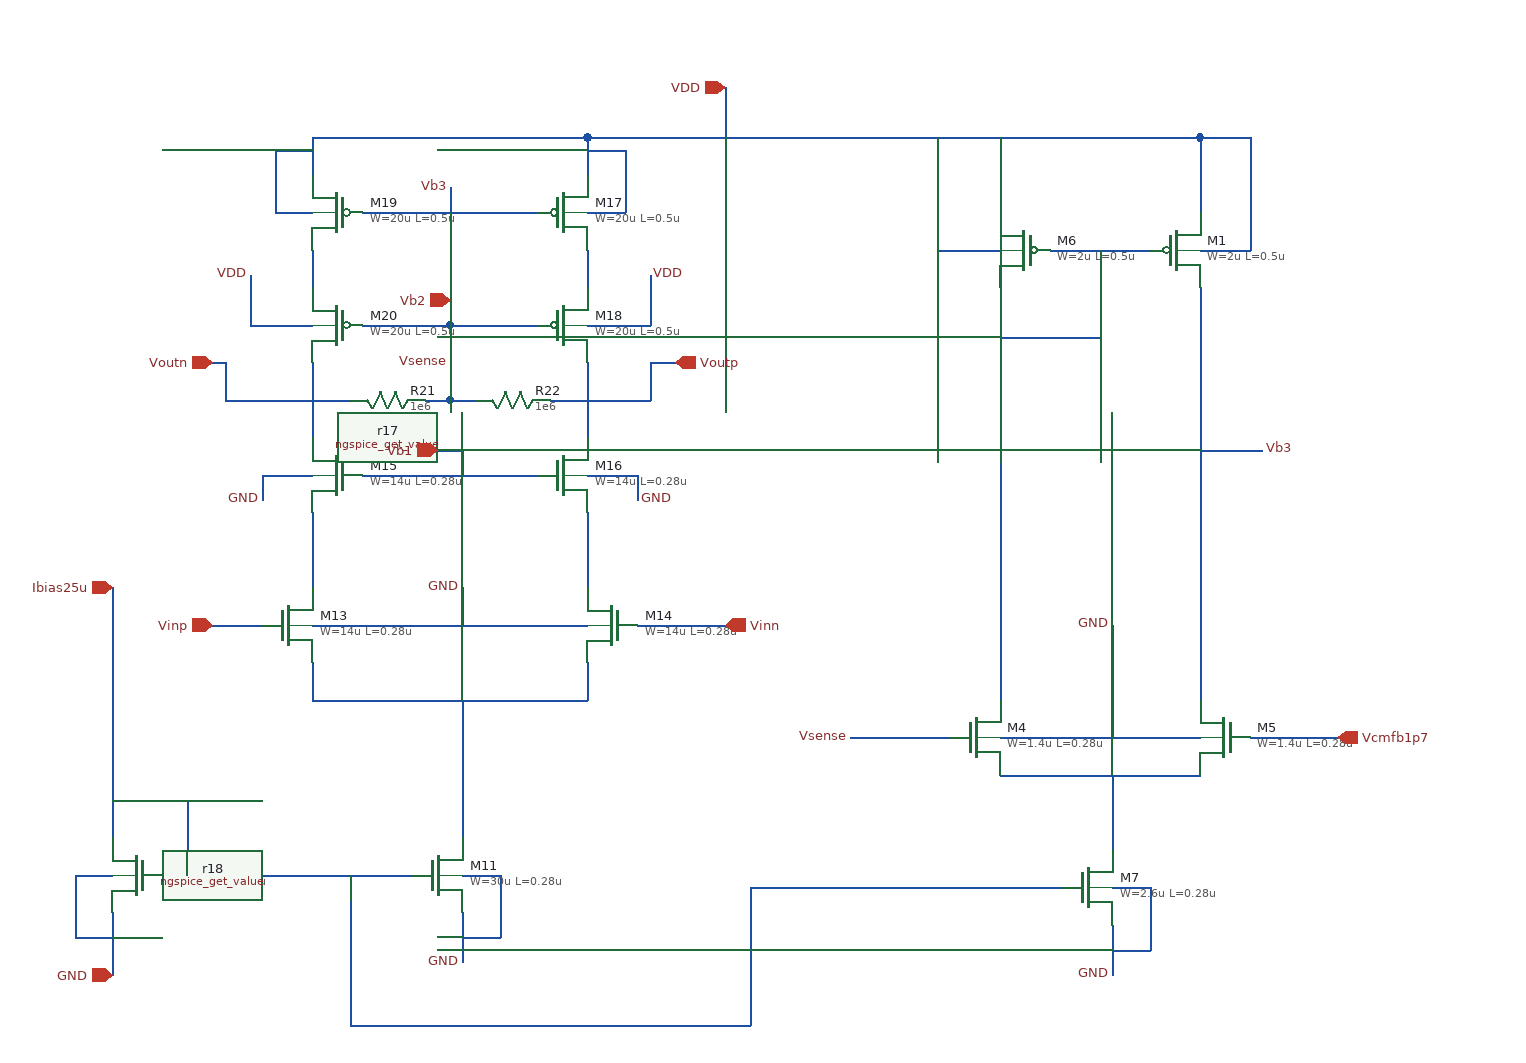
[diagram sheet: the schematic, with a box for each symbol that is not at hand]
v {xschem version=3.4.8RC file_version=1.3}
G {}
K {}
V {}
S {}
F {}
E {}
N 360 -840 490 -840 {lab=Vb3
}
N 490 -840 500 -840 {lab=Vb3
}
N 360 -750 430 -750 {lab=Vb2
}
N 430 -750 500 -750 {lab=Vb2
}
N 540 -810 540 -780 {lab=#net1
}
N 320 -810 320 -780 {lab=#net2
}
N 320 -900 320 -870 {lab=VDD
}
N 320 -900 540 -900 {lab=VDD
}
N 540 -900 540 -870 {lab=VDD
}
N 290 -840 320 -840 {lab=VDD
}
N 290 -890 290 -840 {lab=VDD
}
N 290 -890 320 -890 {lab=VDD
}
N 540 -840 570 -840 {lab=VDD
}
N 570 -890 570 -840 {lab=VDD
}
N 540 -890 570 -890 {lab=VDD
}
N 360 -630 500 -630 {lab=Vb1
}
N 320 -720 320 -660 {lab=Voutn
}
N 540 -720 540 -660 {lab=Voutp
}
N 320 -600 320 -540 {lab=#net3
}
N 540 -600 540 -540 {lab=#net4
}
N 260 -510 280 -510 {lab=Vinp
}
N 580 -510 650 -510 {lab=Vinn
}
N 200 -310 400 -310 {lab=Ibias25u
}
N 320 -470 320 -450 {lab=#net5
}
N 320 -450 540 -450 {lab=#net5
}
N 540 -480 540 -450 {lab=#net5
}
N 320 -480 320 -470 {lab=#net5
}
N 440 -450 440 -400 {lab=#net5
}
N 160 -540 160 -400 {lab=Ibias25u
}
N 160 -370 180 -370 {lab=Ibias25u
}
N 180 -370 220 -370 {lab=Ibias25u
}
N 160 -280 160 -230 {lab=GND
}
N 440 -280 440 -240 {lab=GND
}
N 440 -310 470 -310 {lab=GND
}
N 470 -310 470 -260 {lab=GND
}
N 440 -260 470 -260 {lab=GND
}
N 130 -310 160 -310 {lab=GND
}
N 130 -310 130 -260 {lab=GND
spice_ignore=short}
N 130 -260 160 -260 {lab=GND
}
N 320 -510 540 -510 {lab=GND
}
N 280 -630 320 -630 {lab=GND
}
N 280 -630 280 -610 {lab=GND
}
N 540 -630 580 -630 {lab=GND
}
N 580 -630 580 -610 {lab=GND
}
N 270 -750 320 -750 {lab=VDD
}
N 270 -790 270 -750 {lab=VDD
}
N 540 -750 590 -750 {lab=VDD
}
N 590 -790 590 -750 {lab=VDD
}
N 430 -860 430 -840 {lab=Vb3
}
N 430 -770 430 -750 {lab=Vb2
}
N 440 -650 440 -630 {lab=Vb1
}
N 250 -720 250 -690 {lab=Voutn
}
N 590 -720 610 -720 {lab=Voutp
}
N 590 -720 590 -690 {lab=Voutp
}
N 160 -400 160 -340 {lab=Ibias25u
}
N 220 -370 220 -310 {lab=Ibias25u
}
N 440 -400 440 -340 {lab=#net5
}
N 330 -690 350 -690 {lab=Voutn
}
N 320 -690 330 -690 {lab=Voutn
}
N 510 -690 540 -690 {lab=Voutp
}
N 430 -720 430 -690 {lab=Vsense
spice_ignore=short}
N 410 -690 430 -690 {lab=Vsense
spice_ignore=short}
N 430 -690 450 -690 {lab=Vsense
spice_ignore=short}
N 1030 -900 1030 -840 {lab=VDD}
N 540 -900 860 -900 {lab=VDD}
N 860 -900 960 -900 {lab=VDD}
N 1030 -650 1080 -650 {lab=#net6}
N 910 -810 990 -810 {lab=#net7}
N 870 -900 870 -840 {lab=VDD}
N 960 -270 960 -230 {lab=GND
}
N 960 -300 990 -300 {lab=GND
}
N 990 -300 990 -250 {lab=GND
}
N 960 -250 990 -250 {lab=GND
}
N 350 -310 350 -190 {lab=Ibias25u}
N 350 -190 670 -190 {lab=Ibias25u}
N 670 -300 670 -190 {lab=Ibias25u}
N 840 -300 920 -300 {lab=Ibias25u}
N 750 -300 840 -300 {lab=Ibias25u}
N 670 -300 750 -300 {lab=Ibias25u}
N 750 -420 830 -420 {lab=Vsense}
N 1070 -420 1140 -420 {lab=Vcmfb1p7}
N 890 -390 1030 -390 {lab=#net8}
N 960 -390 960 -330 {lab=#net8}
N 1030 -780 1030 -450 {lab=#net6}
N 870 -780 870 -450 {lab=#net7}
N 870 -390 890 -390 {lab=#net8}
N 960 -900 1030 -900 {lab=VDD}
N 820 -810 870 -810 {lab=VDD}
N 820 -900 820 -810 {lab=VDD}
N 1030 -810 1070 -810 {lab=VDD}
N 1070 -900 1070 -810 {lab=VDD}
N 1030 -900 1070 -900 {lab=VDD}
N 870 -420 1030 -420 {lab=GND}
N 950 -810 950 -740 {lab=#net7}
N 870 -740 950 -740 {lab=#net7}
N 650 -940 650 -900 {lab=VDD}
N 250 -690 320 -690 {lab=Voutn}
N 540 -690 590 -690 {lab=Voutp}
N 240 -720 250 -720 {lab=Voutn}
N 420 -650 440 -650 {lab=Vb1}
N 240 -510 260 -510 {lab=Vinp}
N 960 -510 960 -420 {lab=GND}
N 440 -540 440 -510 {lab=GND}
C {lab_pin.sym} 430 -860 0 0 {name=p23 sig_type=std_logic lab=Vb3
}
C {symbols/nfet_03v3.sym} 420 -310 0 0 {name=M11
L=0.28u
W=30u
nf=1
m=1
ad="'int((nf+1)/2) * W/nf * 0.18u'"
pd="'2*int((nf+1)/2) * (W/nf + 0.18u)'"
as="'int((nf+2)/2) * W/nf * 0.18u'"
ps="'2*int((nf+2)/2) * (W/nf + 0.18u)'"
nrd="'0.18u / W'" nrs="'0.18u / W'"
sa=0 sb=0 sd=0
model=nfet_03v3
spiceprefix=X
}
C {symbols/nfet_03v3.sym} 180 -310 0 1 {name=M12
L=0.28u
W=2.6u
nf=1
m=1
ad="'int((nf+1)/2) * W/nf * 0.18u'"
pd="'2*int((nf+1)/2) * (W/nf + 0.18u)'"
as="'int((nf+2)/2) * W/nf * 0.18u'"
ps="'2*int((nf+2)/2) * (W/nf + 0.18u)'"
nrd="'0.18u / W'" nrs="'0.18u / W'"
sa=0 sb=0 sd=0
model=nfet_03v3
spiceprefix=X
}
C {symbols/nfet_03v3.sym} 300 -510 0 0 {name=M13
L=0.28u
W=14u
nf=1
m=1
ad="'int((nf+1)/2) * W/nf * 0.18u'"
pd="'2*int((nf+1)/2) * (W/nf + 0.18u)'"
as="'int((nf+2)/2) * W/nf * 0.18u'"
ps="'2*int((nf+2)/2) * (W/nf + 0.18u)'"
nrd="'0.18u / W'" nrs="'0.18u / W'"
sa=0 sb=0 sd=0
model=nfet_03v3
spiceprefix=X
}
C {symbols/nfet_03v3.sym} 560 -510 0 1 {name=M14
L=0.28u
W=14u
nf=1
m=1
ad="'int((nf+1)/2) * W/nf * 0.18u'"
pd="'2*int((nf+1)/2) * (W/nf + 0.18u)'"
as="'int((nf+2)/2) * W/nf * 0.18u'"
ps="'2*int((nf+2)/2) * (W/nf + 0.18u)'"
nrd="'0.18u / W'" nrs="'0.18u / W'"
sa=0 sb=0 sd=0
model=nfet_03v3
spiceprefix=X
}
C {symbols/nfet_03v3.sym} 340 -630 0 1 {name=M15
L=0.28u
W=14u
nf=1
m=1
ad="'int((nf+1)/2) * W/nf * 0.18u'"
pd="'2*int((nf+1)/2) * (W/nf + 0.18u)'"
as="'int((nf+2)/2) * W/nf * 0.18u'"
ps="'2*int((nf+2)/2) * (W/nf + 0.18u)'"
nrd="'0.18u / W'" nrs="'0.18u / W'"
sa=0 sb=0 sd=0
model=nfet_03v3
spiceprefix=X
}
C {symbols/nfet_03v3.sym} 520 -630 0 0 {name=M16
L=0.28u
W=14u
nf=1
m=1
ad="'int((nf+1)/2) * W/nf * 0.18u'"
pd="'2*int((nf+1)/2) * (W/nf + 0.18u)'"
as="'int((nf+2)/2) * W/nf * 0.18u'"
ps="'2*int((nf+2)/2) * (W/nf + 0.18u)'"
nrd="'0.18u / W'" nrs="'0.18u / W'"
sa=0 sb=0 sd=0
model=nfet_03v3
spiceprefix=X
}
C {symbols/pfet_03v3.sym} 520 -840 0 0 {name=M17
L=0.5u
W=20u
nf=1
m=1
ad="'int((nf+1)/2) * W/nf * 0.18u'"
pd="'2*int((nf+1)/2) * (W/nf + 0.18u)'"
as="'int((nf+2)/2) * W/nf * 0.18u'"
ps="'2*int((nf+2)/2) * (W/nf + 0.18u)'"
nrd="'0.18u / W'" nrs="'0.18u / W'"
sa=0 sb=0 sd=0
model=pfet_03v3
spiceprefix=X
}
C {symbols/pfet_03v3.sym} 520 -750 0 0 {name=M18
L=0.5u
W=20u
nf=1
m=1
ad="'int((nf+1)/2) * W/nf * 0.18u'"
pd="'2*int((nf+1)/2) * (W/nf + 0.18u)'"
as="'int((nf+2)/2) * W/nf * 0.18u'"
ps="'2*int((nf+2)/2) * (W/nf + 0.18u)'"
nrd="'0.18u / W'" nrs="'0.18u / W'"
sa=0 sb=0 sd=0
model=pfet_03v3
spiceprefix=X
}
C {symbols/pfet_03v3.sym} 340 -840 0 1 {name=M19
L=0.5u
W=20u
nf=1
m=1
ad="'int((nf+1)/2) * W/nf * 0.18u'"
pd="'2*int((nf+1)/2) * (W/nf + 0.18u)'"
as="'int((nf+2)/2) * W/nf * 0.18u'"
ps="'2*int((nf+2)/2) * (W/nf + 0.18u)'"
nrd="'0.18u / W'" nrs="'0.18u / W'"
sa=0 sb=0 sd=0
model=pfet_03v3
spiceprefix=X
}
C {symbols/pfet_03v3.sym} 340 -750 0 1 {name=M20
L=0.5u
W=20u
nf=1
m=1
ad="'int((nf+1)/2) * W/nf * 0.18u'"
pd="'2*int((nf+1)/2) * (W/nf + 0.18u)'"
as="'int((nf+2)/2) * W/nf * 0.18u'"
ps="'2*int((nf+2)/2) * (W/nf + 0.18u)'"
nrd="'0.18u / W'" nrs="'0.18u / W'"
sa=0 sb=0 sd=0
model=pfet_03v3
spiceprefix=X
}
C {ngspice_get_value.sym} 540 -670 0 0 {name=r17 node=i(@m.xm16.m0[id])
descr="I="
}
C {ngspice_get_value.sym} 320 -670 0 0 {name=r18 node=i(@m.xm15.m0[id])
descr="I="
}
C {res.sym} 380 -690 1 0 {name=R21
value=1e6
footprint=1206
device=resistor
m=1
}
C {res.sym} 480 -690 1 0 {name=R22
value=1e6
footprint=1206
device=resistor
m=1
}
C {lab_pin.sym} 430 -720 0 0 {name=p32 sig_type=std_logic lab=Vsense
}
C {symbols/pfet_03v3.sym} 1010 -810 0 0 {name=M1
L=0.5u
W=2u
nf=1
m=1
ad="'int((nf+1)/2) * W/nf * 0.18u'"
pd="'2*int((nf+1)/2) * (W/nf + 0.18u)'"
as="'int((nf+2)/2) * W/nf * 0.18u'"
ps="'2*int((nf+2)/2) * (W/nf + 0.18u)'"
nrd="'0.18u / W'" nrs="'0.18u / W'"
sa=0 sb=0 sd=0
model=pfet_03v3
spiceprefix=X
}
C {symbols/nfet_03v3.sym} 850 -420 0 0 {name=M4
L=0.28u
W=1.4u
nf=1
m=1
ad="'int((nf+1)/2) * W/nf * 0.18u'"
pd="'2*int((nf+1)/2) * (W/nf + 0.18u)'"
as="'int((nf+2)/2) * W/nf * 0.18u'"
ps="'2*int((nf+2)/2) * (W/nf + 0.18u)'"
nrd="'0.18u / W'" nrs="'0.18u / W'"
sa=0 sb=0 sd=0
model=nfet_03v3
spiceprefix=X
}
C {symbols/nfet_03v3.sym} 1050 -420 0 1 {name=M5
L=0.28u
W=1.4u
nf=1
m=1
ad="'int((nf+1)/2) * W/nf * 0.18u'"
pd="'2*int((nf+1)/2) * (W/nf + 0.18u)'"
as="'int((nf+2)/2) * W/nf * 0.18u'"
ps="'2*int((nf+2)/2) * (W/nf + 0.18u)'"
nrd="'0.18u / W'" nrs="'0.18u / W'"
sa=0 sb=0 sd=0
model=nfet_03v3
spiceprefix=X
}
C {lab_pin.sym} 750 -420 0 0 {name=p3 sig_type=std_logic lab=Vsense
}
C {symbols/pfet_03v3.sym} 890 -810 0 1 {name=M6
L=0.5u
W=2u
nf=1
m=1
ad="'int((nf+1)/2) * W/nf * 0.18u'"
pd="'2*int((nf+1)/2) * (W/nf + 0.18u)'"
as="'int((nf+2)/2) * W/nf * 0.18u'"
ps="'2*int((nf+2)/2) * (W/nf + 0.18u)'"
nrd="'0.18u / W'" nrs="'0.18u / W'"
sa=0 sb=0 sd=0
model=pfet_03v3
spiceprefix=X
}
C {symbols/nfet_03v3.sym} 940 -300 0 0 {name=M7
L=0.28u
W=2.6u
nf=1
m=1
ad="'int((nf+1)/2) * W/nf * 0.18u'"
pd="'2*int((nf+1)/2) * (W/nf + 0.18u)'"
as="'int((nf+2)/2) * W/nf * 0.18u'"
ps="'2*int((nf+2)/2) * (W/nf + 0.18u)'"
nrd="'0.18u / W'" nrs="'0.18u / W'"
sa=0 sb=0 sd=0
model=nfet_03v3
spiceprefix=X
}
C {ipin.sym} 160 -540 0 0 {name=p4 lab=Ibias25u}
C {ipin.sym} 650 -940 0 0 {name=p5 lab=VDD}
C {ipin.sym} 1140 -420 0 1 {name=p7 lab=Vcmfb1p7}
C {ipin.sym} 430 -770 0 0 {name=p10 lab=Vb2}
C {lab_pin.sym} 270 -790 0 0 {name=p11 sig_type=std_logic lab=VDD
}
C {lab_pin.sym} 590 -790 0 1 {name=p13 sig_type=std_logic lab=VDD
}
C {ipin.sym} 420 -650 0 0 {name=p12 lab=Vb1}
C {ipin.sym} 240 -510 0 0 {name=p6 lab=Vinp}
C {ipin.sym} 650 -510 0 1 {name=p1 lab=Vinn}
C {opin.sym} 610 -720 0 0 {name=p15 lab=Voutp}
C {opin.sym} 240 -720 0 1 {name=p16 lab=Voutn}
C {lab_pin.sym} 280 -610 0 0 {name=p17 sig_type=std_logic lab=GND}
C {lab_pin.sym} 580 -610 0 1 {name=p18 sig_type=std_logic lab=GND}
C {lab_pin.sym} 440 -240 0 0 {name=p20 sig_type=std_logic lab=GND}
C {lab_pin.sym} 960 -230 0 0 {name=p21 sig_type=std_logic lab=GND}
C {lab_pin.sym} 960 -510 0 0 {name=p8 sig_type=std_logic lab=GND}
C {lab_pin.sym} 440 -540 0 0 {name=p22 sig_type=std_logic lab=GND}
C {ipin.sym} 160 -230 0 0 {name=p9 lab=GND}
C {lab_pin.sym} 1080 -650 0 1 {name=p2 sig_type=std_logic lab=Vb3}
